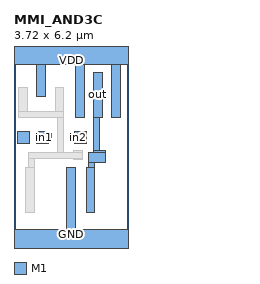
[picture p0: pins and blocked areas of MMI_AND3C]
MACRO MMI_AND3C
	CLASS CORE ;
	FOREIGN MMI_AND3C 0 0 ;
	SIZE 3.72 BY 6.2 ;
	SYMMETRY X Y ;
	SITE CORE1 ;
	PIN out
		DIRECTION output ;
		USE SIGNAL ;
		PORT
			LAYER M1 ;
			RECT 2.595 4.07 2.875 5.54 ;
			LAYER M1 ;
			RECT 2.6 2.98 2.79 4.07 ;
			LAYER M1 ;
			RECT 2.6 2.93 2.98 2.98 ;
			LAYER M1 ;
			RECT 2.435 2.6 2.98 2.93 ;
			LAYER M1 ;
			RECT 2.435 2.445 2.63 2.6 ;
			LAYER M1 ;
			RECT 2.35 0.975 2.63 2.445 ;
		END
		AntennaDiffArea 1.2859 ;
	END out
	PIN in1
		DIRECTION input ;
		USE SIGNAL ;
		PORT
			LAYER M1 ;
			RECT 0.74 3.545 1.12 3.6 ;
			LAYER M1 ;
			RECT 0.74 3.265 1.23 3.545 ;
			LAYER M1 ;
			RECT 0.74 3.22 1.12 3.265 ;
		END
		AntennaGateArea 0.39 ;
	END in1
	PIN GND
		DIRECTION inout ;
		USE GROUND ;
		PORT
			LAYER M1 ;
			RECT 1.715 0.42 1.995 2.445 ;
			LAYER M1 ;
			RECT 0 -0.42 3.72 0.42 ;
		END
	END GND
	PIN in2
		DIRECTION input ;
		USE SIGNAL ;
		PORT
			LAYER M1 ;
			RECT 1.98 3.55 2.36 3.6 ;
			LAYER M1 ;
			RECT 1.82 3.27 2.36 3.55 ;
			LAYER M1 ;
			RECT 1.98 3.22 2.36 3.27 ;
		END
		AntennaGateArea 0.39 ;
	END in2
	PIN VDD
		DIRECTION inout ;
		USE POWER ;
		PORT
			LAYER M1 ;
			RECT 0 5.78 3.72 6.62 ;
			LAYER M1 ;
			RECT 0.75 4.76 1.03 5.78 ;
			LAYER M1 ;
			RECT 2.005 4.07 2.285 5.78 ;
			LAYER M1 ;
			RECT 3.185 4.07 3.465 5.78 ;
		END
	END VDD
	PIN in0
		DIRECTION input ;
		USE SIGNAL ;
		PORT
			LAYER M1 ;
			RECT 0.12 3.22 0.5 3.6 ;
		END
		AntennaGateArea 0.39 ;
	END in0
	OBS
		LAYER M1 ;
		RECT 0.16 4.26 0.44 5.04 ;
		LAYER M1 ;
		RECT 1.34 4.26 1.62 5.04 ;
		LAYER M1 ;
		RECT 0.16 4.07 1.62 4.26 ;
		LAYER M1 ;
		RECT 1.43 2.93 1.62 4.07 ;
		LAYER M1 ;
		RECT 1.95 2.93 2.23 2.97 ;
		LAYER M1 ;
		RECT 0.465 2.735 2.23 2.93 ;
		LAYER M1 ;
		RECT 0.465 2.445 0.66 2.735 ;
		LAYER M1 ;
		RECT 1.95 2.69 2.23 2.735 ;
		LAYER M1 ;
		RECT 0.385 0.955 0.665 2.445 ;
	END
END MMI_AND3C
